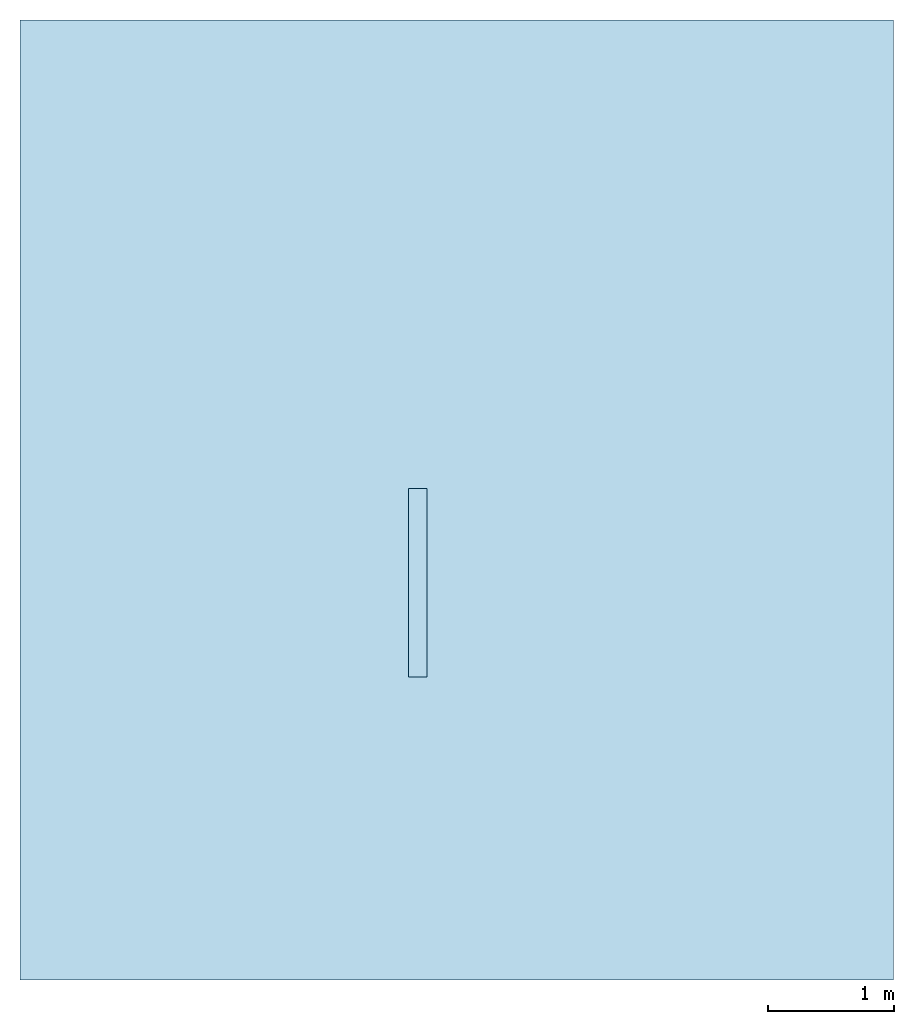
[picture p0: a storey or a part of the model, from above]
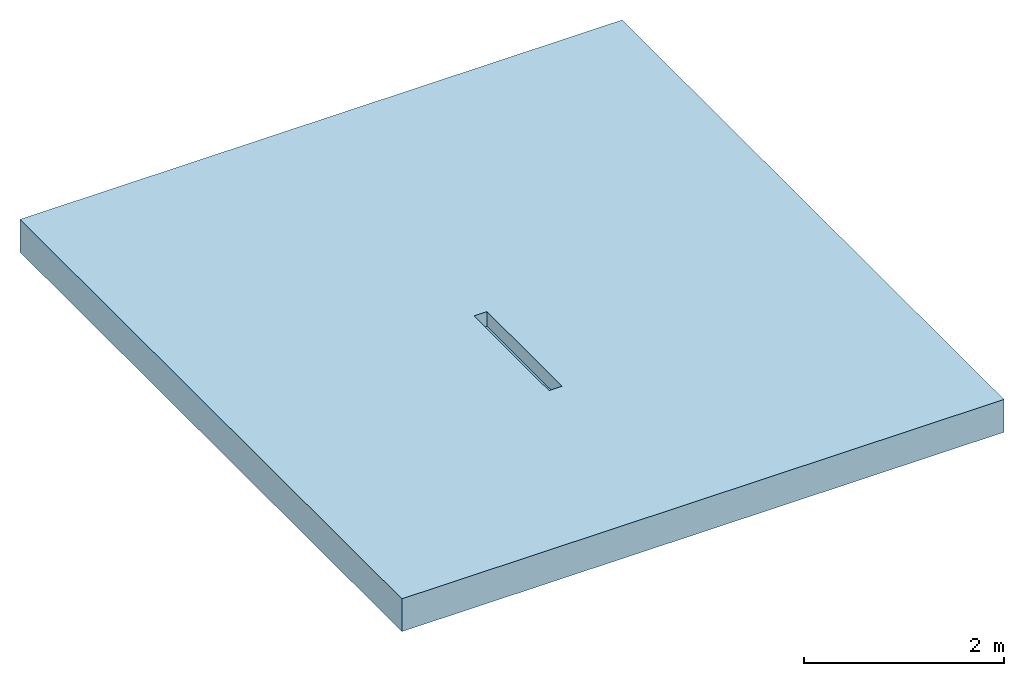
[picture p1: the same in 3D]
Properties of the parts of a building model (IFC2X3)

# File
Description: ViewDefinition [CoordinationView]
File name: 7996 - Flush RH drop kerb - 1500mm LG.ifc
Time: 2013-09-12T12:47:02
Written by: Autodesk Revit 2013
Made in: 20120221_2030(x64)

# IfcProject, Project Number
LongName: Project Name; Phase: Project Status

# IfcSite, Default
RefLatitude: 42, 21, 30, 344238; RefLongitude: -71, -3, -35, -194702; RefElevation: 0 mm

# IfcBuilding
Pset_BuildingCommon - NumberOfStoreys: 2
Other - Project Status: Project Status; Project Number: Project Number; Client Name: Owner; Project Issue Date: Issue Date; Project Name: Project Name; Project Address: Enter address here

# IfcBuildingStorey (2)
Constraints - Elevation Base: 0
Graphics - Symbol: M_Level Head - Circle: M_Level Head - Circle; Symbol at End 1 Default: no; Line Weight: 1; Color: 0; Line Pattern: Center; Symbol at End 2 Default: yes
Identity Data - Structural: no; Building Story: yes
Dimensions - Computation Height: 0 mm
Name | LongName = Name | Elevation (mm) = Constraints, Elevation (mm)
T.O. Fnd. Wall | T.O. Fnd. Wall | -300
Level 1 | Level 1 | 0

# IfcBuildingElementProxy: 7996 - Flush RH drop kerb - 1500mm LG, Civil-Drainage-Channel-ACO-KerbDrain-HB305 - PART 1:7996 - Flush RH drop kerb - 1500mm LG:7996 - Flush RH drop kerb - 1500mm LG:255899
In: T.O. Fnd. Wall
Material: ACO Polymer Concrete.
Other - Revision: 1; CreatedBy: www.aco.co.uk
Construction - KDHB305 - Drainable centre stone: no; I/O Pipe: no; KDHB305 - RH Inlet/outlet end cap: no; KDHB305 - Blind unit: no; KDHB305 - Channel unit - 250mm: no; KDHB305 - Flush LH dropkerb: no; KDHB305 - LH drop kerb: no; KDHB305 - Flush RH dropkerb: yes; KDHB305 - Channel unit - 500mm: no; KDHB305 - Centre stone: no; KDHB305 - Channel unit - 1000mm: no; KDHB305 - Perforated centre stone: no; KDHB305 - Closing end cap: no; KDHB305 - RH drop kerb: no; KDHB305 - Access Unit: no; KDHB305 - LH Inlet/Outlet end cap: no
Constraints - Moves With Nearby Elements: no; Level: Level: Level 1
Phasing - Phase Created: Phase 1
Dimensions - Volume: 34482481 mm3; I/O Endcap Void depth: 6000 mm; Staright Void Depth: -180 mm; Void_Length: 1500 mm; Void_Width: 150 mm
Pset_BuildingElementProxyCommon - Reference: 7996 - Flush RH drop kerb - 1500mm LG
Identity Data - E-mail Technical: technical@aco.co.uk; Product brochure: http://www.aco.co.uk/download.php?id=120; Model: ACO KerbDrain HB305; Address: ACO Business Park, Hitchin Road, Shefford, Bedfordshire, United Kingdom SG17 5TE; Cost: 0; Product Code: 7996; Model Description: Combined kerb and drainage system; OmniClass Number: 23.70.50.24; Assembly Description: Rain Water Drainage; Type Comments: ACO KerbDrain HB305 half battered flush drainable right-hand drainable drop kerb assembly 1500mm; Price: POA - contact ACO; OmniClass Title: Rainwater Removal; Installation guidelines: http://www.aco.co.uk/download.php?id=120; Fax: +44 (0)1462 815895; Manufacturer: ACO Technologies plc - ACO Water Management Division; Telephone: +44 (0)1462 816666; Assembly Code: D2040; Maintenance guidelines: http://www.aco.co.uk/download.php?id=120; URL: www.aco.co.uk; E-mail Sales: customersupport@aco.co.uk; Product Page URL: http://www.aco.co.uk/product_detail.php?id=3
Materials and Finishes - End Cap Colour: N/A; Access Cover/Frame Colour: N/A; Channel Material: Vienite® Synthetic Resin Concrete; Access Cover/Frame Finish: N/A; End Cap Material: N/A; Connection Pipe Material: N/A; Access Cover/Frame Material: N/A; Channel Colour: Grey; Connection Pipe Material Colour: N/A
Data - Channel C.S.A: 0.02 to 0.008mm²; Drainage Slot Intake area: N/A; Product Dimensions: 1500mm x 150mm x 305/180mm (LxWxH); Hydraulic Performance: http://www.aco.co.uk/download.php?id=120; Installation - Concrete Grade: Refer to brochure; Product Weight: 75.5 Kg; Connection Pipe O.D: N/A; Concrete Surround Volume - Load Class A 15 - D 400 - Grass or Asphalt Pavement: N/A; Concrete Surround Volume - Load Class A 15 - D 400 - Concrete Pavement: N/A; Load Class: A 15 - D 400; Product Standard: BS EN 1433:2002, CE marked, Kitemarked; Drainage Slot Width: N/A; Invert Depth: 280/155mm; ACO Hydraulic Design Software: http://www.acodesign.co.uk
General - TagNumber: 0.000000; SerialNumber: 0.000000
Green Building Properties - Access Cover/Frame Recycled Material Content: N/A; End Cap Recyclable: N/A; End Cap Recycled Material Content: N/A; Channel Recycled Material Content: 20% minimum; Channel Recyclable: Fully recyclable; Access Cover/Frame Recyclable: N/A

# IfcOpeningElement: Recess (2)
In: Level 1
Dimensions - Thickness: 400 mm; Perimeter: 29157.2 mm; Volume: 21165932206 mm3; Area: 53016081 mm2
Constraints - Room Bounding: yes; Related to Mass: no; Height Offset From Level: 0 mm; Level: Level: Level 1
Phasing - Phase Created: Phase 1
Structural - Enable Analytical Model: no; Structural: no
Graphics - Coarse Scale Fill Color: 0
Construction - Default Thickness: 400 mm; Function: 0
Analytical Properties - Absorptance: 0.1; Roughness: 1

# IfcSlab: Floor:Generic Floor - 400mm, Floor:Generic Floor - 400mm:184025
In: Level 1
PredefinedType: FLOOR; Material: Default Floor 400 mm
Dimensions - Thickness: 400 mm; Perimeter: 29157.2 mm; Volume: 21165932206 mm3; Area: 53016081 mm2
Constraints - Room Bounding: yes; Related to Mass: no; Height Offset From Level: 0 mm; Level: Level: Level 1
Phasing - Phase Created: Phase 1
Structural - Enable Analytical Model: no; Structural: no
Pset_SlabCommon - Reference: Generic Floor - 400mm; IsExternal: no; LoadBearing: yes
Graphics - Coarse Scale Fill Color: 0
Construction - Default Thickness: 400 mm; Function: 0
Analytical Properties - Absorptance: 0.1; Roughness: 1
